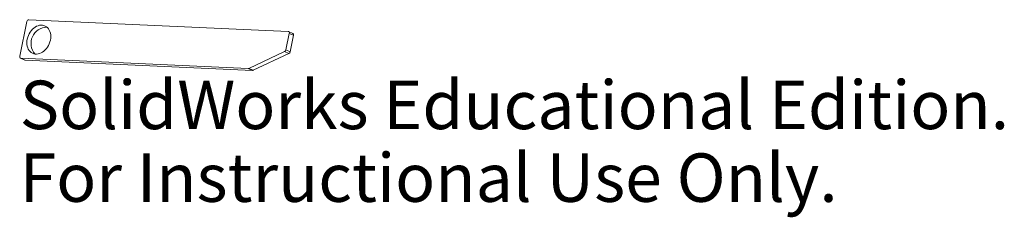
# Model space of a CAD drawing. Units: millimetres. Extents: x -26.5 to 71.6, y -14.5 to 5.2.
import ezdxf

# ---------------------------------------------------------------- set-up
doc = ezdxf.new("R2010")
doc.units = ezdxf.units.MM
doc.styles.add('SLDTEXTSTYLE0', font='TXT', dxfattribs={"width": 0.7})

msp = doc.modelspace()

# ---------------------------------------------------------------- linework, layer by layer
at = {"color": 7, "linetype": 'Continuous', "lineweight": 15}
for p, q in [((-25.81, 5.024), (-26.527, 1.562)), ((0.218, 4.044), (-25.616, 5.209)), ((0.685, 3.844), (0.26, 4.034)), ((-0.008, 2.203), (0.332, 3.845)), ((0.758, 3.655), (0.332, 3.845)), ((0.417, 2.013), (0.758, 3.655)), ((-0.134, 2.032), (-3.694, 0.355)), ((0.291, 1.842), (-0.134, 2.032)), ((-0.008, 2.203), (0.417, 2.013)), ((-26.455, 1.372), (-26.03, 1.182)), ((-26.413, 1.362), (-3.762, 0.341)), ((-26.413, 1.362), (-25.988, 1.172)), ((-25.988, 1.172), (-3.337, 0.15)), ((0.291, 1.842), (-3.269, 0.165)), ((-3.337, 0.15), (-3.762, 0.341)), ((-3.694, 0.355), (-3.269, 0.165))]:
    msp.add_line(p, q, dxfattribs=at)
at = {"color": 7, "linetype": 'Continuous', "lineweight": 15, "flags": 128}
for points in [[(-23.477, 3.171), (-23.449, 3.353), (-23.439, 3.532), (-23.448, 3.706), (-23.476, 3.873), (-23.522, 4.029), (-23.585, 4.173), (-23.665, 4.302), (-23.76, 4.414), (-23.869, 4.507), (-23.99, 4.579), (-24.121, 4.631), (-24.26, 4.66), (-24.405, 4.666), (-24.553, 4.65), (-24.703, 4.611), (-24.851, 4.551), (-24.996, 4.469), (-25.135, 4.368), (-25.267, 4.249), (-25.388, 4.113), (-25.497, 3.964), (-25.593, 3.803), (-25.673, 3.633), (-25.737, 3.456), (-25.784, 3.275), (-25.812, 3.094), (-25.822, 2.915), (-25.813, 2.741), (-25.785, 2.574), (-25.74, 2.417), (-25.676, 2.274), (-25.596, 2.145), (-25.501, 2.033), (-25.392, 1.94), (-25.272, 1.867), (-25.141, 1.816), (-25.002, 1.787), (-24.857, 1.78), (-24.708, 1.797), (-24.559, 1.835), (-24.41, 1.896), (-24.265, 1.977), (-24.126, 2.079), (-23.995, 2.198), (-23.873, 2.333), (-23.764, 2.483), (-23.668, 2.644), (-23.588, 2.814), (-23.524, 2.991), (-23.477, 3.171)], [(-25.988, 1.172), (-26.017, 1.177), (-26.03, 1.182)]]:
    msp.add_lwpolyline(points, dxfattribs=at)
at = {"color": 7, "linetype": 'Continuous', "lineweight": 15}
for centre, radius, start, end in [((-25.596, 4.995), 0.216, 95.29199, 172.22075), ((-23.788, 2.847), 1.621, 91.08992, 220.72007), ((0.193, 3.897), 0.149, 339.35518, 80.14682), ((0.6, 3.703), 0.165, 342.96088, 58.71198), ((-0.248, 2.248), 0.244, 297.82986, 349.32207), ((0.177, 2.058), 0.244, 297.82986, 349.32207), ((-26.388, 1.509), 0.149, 159.35518, 260.14682), ((-3.758, 0.484), 0.144, 268.24143, 296.0403), ((-3.332, 0.294), 0.144, 268.24143, 296.0403)]:
    msp.add_arc(centre, radius, start, end, dxfattribs=at)

# ---------------------------------------------------------------- texts
at = {"color": 7, "linetype": 'Continuous', "char_height": 4.83362, "attachment_point": 1, "style": 'SLDTEXTSTYLE0'}
for s, insert in [('SolidWorks Educational Edition.', (-26.537, -0.869)), ('For Instructional Use Only.', (-26.537, -8.12))]:
    msp.add_mtext(s, dxfattribs=dict(at, insert=insert))

doc.saveas('drawing.dxf')
